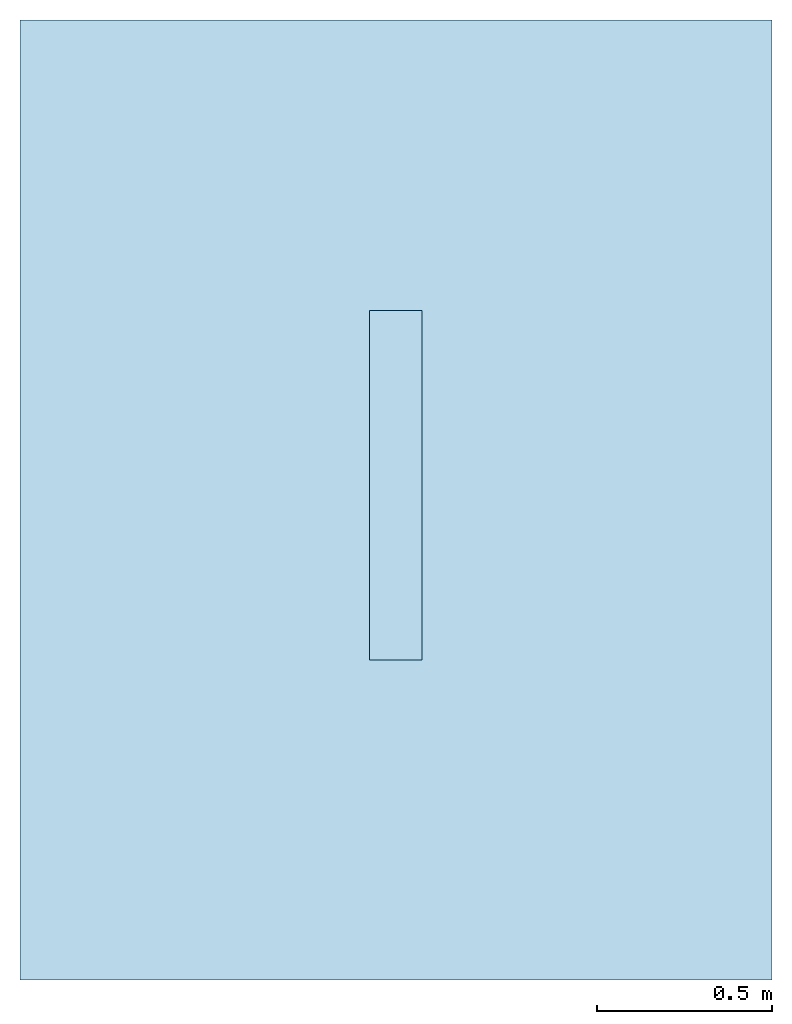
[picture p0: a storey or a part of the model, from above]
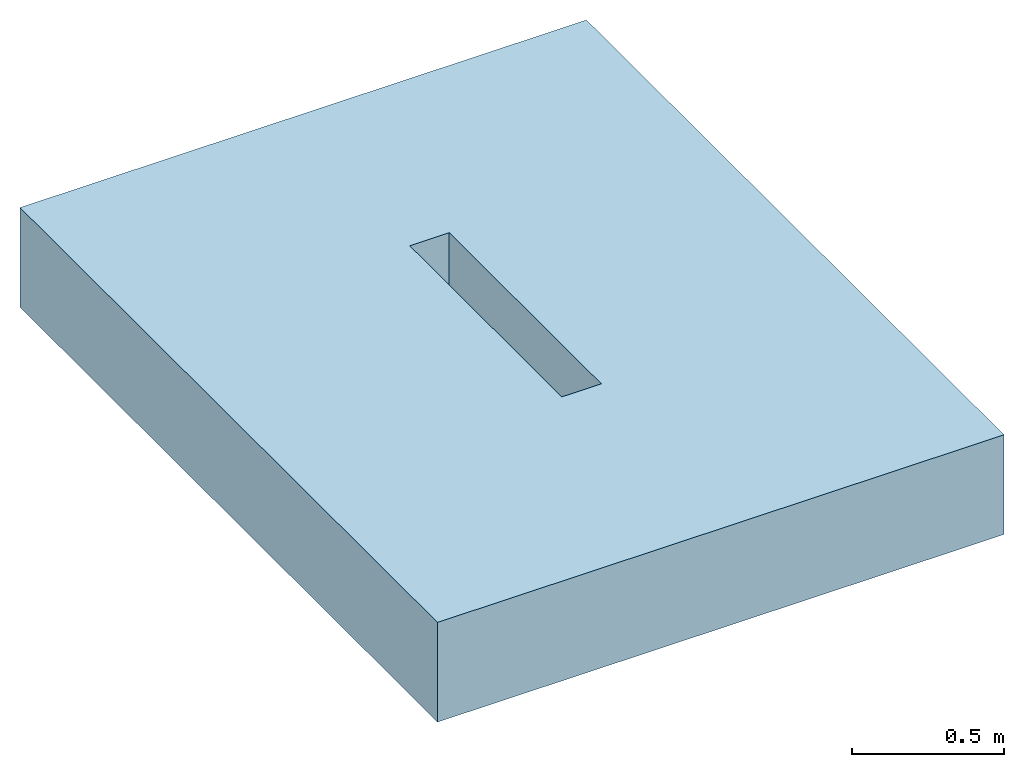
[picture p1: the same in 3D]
Properties of the parts of a building model (IFC2X3)

# File
Description: ViewDefinition [CoordinationView]
File name: 4966 - RH BS transition kerb - 1000mm LG.ifc
Time: 2013-09-18T16:27:48
Written by: Autodesk Revit 2013
Made in: 20120221_2030(x64)

# IfcProject, Project Number
LongName: Project Name; Phase: Project Status

# IfcSite, Default
RefLatitude: 42, 21, 30, 344238; RefLongitude: -71, -3, -35, -194702; RefElevation: 0 mm

# IfcBuilding
Pset_BuildingCommon - NumberOfStoreys: 2
Other - Project Name: Project Name; Project Number: Project Number; Project Status: Project Status; Project Address: Enter address here; Project Issue Date: Issue Date; Client Name: Owner

# IfcBuildingStorey (2)
Constraints - Elevation Base: 0
Graphics - Symbol at End 2 Default: yes; Symbol at End 1 Default: no; Line Pattern: Center; Line Weight: 1; Color: 0; Symbol: M_Level Head - Circle: M_Level Head - Circle
Identity Data - Structural: no; Building Story: yes
Dimensions - Computation Height: 0 mm
Name | LongName = Name | Elevation (mm) = Constraints, Elevation (mm)
T.O. Fnd. Wall | T.O. Fnd. Wall | -300
Level 1 | Level 1 | 0

# IfcBuildingElementProxy: 4966 - RH BS transition kerb - 1000mm LG, Civil-Drainage-Channel-ACO-KerbDrain-HB480(amar):4966 - RH BS transition kerb - 1000mm LG:4966 - RH BS transition kerb - 1000mm LG:481515
In: T.O. Fnd. Wall
Material: ACO Polymer Concrete.
Other - CreatedBy: www.aco.co.uk; Revision: 1
Green Building Properties - End Cap Recycled Material Content: N/A; Access Cover/Frame Recycled Material Content: N/A; Channel Recycled Material Content: 20% minimum; Access Cover/Frame Recyclable: N/A; Channel Recyclable: Fully recyclable; End Cap Recyclable: N/A
Constraints - Moves With Nearby Elements: no; Level: Level: Level 1
Dimensions - Volume: 38825786 mm3; Void Width: 150 mm; Void Start I/O: 0 mm; junction void depth: 2000 mm; Mitre Small End: 487 mm; Void End I/O: 150 mm; Mitre Void End: -7885 mm; Straight Void Start: 0 mm; Junction End: 150 mm; Mitre Long end: 500 mm; Void Depth: -355 mm; Mitre Void Start: -7880 mm; Junction Start: 0 mm; I/O endcap void depth: 2000 mm; Void Length: 1000 mm
Phasing - Phase Created: Phase 1
Pset_BuildingElementProxyCommon - Reference: 4966 - RH BS transition kerb - 1000mm LG
Identity Data - Product brochure: http://www.aco.co.uk/download.php?id=120; Installation guidelines: http://www.aco.co.uk/download.php?id=120; Type Comments: ACO KerbDrain HB480 half battered RH bus stop transition kerb unit 1000mm long; Maintenance guidelines: http://www.aco.co.uk/download.php?id=120; e-mail Sales: customersupport@aco.co.uk; OmniClass Title: Rainwater Removal; Manufacturer: ACO Technologies plc - ACO Water Management Division; Price: POA - contact ACO; Model Description: Combined kerb and drainage system; Product Code: 4966; Address: ACO Business Park, Hitchin Road, Shefford, Bedfordshire, United Kingdom SG17 5TE; URL: www.aco.co.uk; Assembly Description: Rain Water Drainage; e-mail Technical: technical@aco.co.uk; Assembly Code: D2040; Product Page URL: http://www.aco.co.uk/product_detail.php?id=3; Fax: +44 (0)1462 815895; Telephone: +44 (0)1462 816666; OmniClass Number: 23.70.50.24; Model: ACO KerbDrain HB480; Cost: 0
Materials and Finishes - End Cap Colour: N/A; Access Cover/Frame Finish: N/A; Access Cover/Frame Material: N/A; Connection Pipe Material Colour: N/A; Access Cover/Frame Colour: N/A; Channel Material: Vienite® Synthetic Resin Concrete; End Cap Material: N/A; Channel Colour: Grey; Connection Pipe Material: N/A
Data - Connection Pipe O.D: N/A; Product Dimensions: 1000mm x 150mm x 535/480mm (LxWxH); Load Class: A 15 - D 400; Product Standard: BS EN 1433:2002, CE marked, Kitemarked; Drainage Slot Width: N/A; Installation - Concrete Grade: Refer to brochure; Concrete Surround Volume - Load Class A 15 - D 400 - Concrete Pavement: 0.20m³/m; Concrete Surround Volume - Load Class A 15 - D 400 - Grass or Asphalt Pavement: 0.19m³/m; Channel C.S.A: 0.04m²; Hydraulic Performance: http://www.aco.co.uk/download.php?id=120; Drainage Slot Intake area: N/A; Product Weight: 83.4 kg; ACO Hydraulic Design Software: http://www.acodesign.co.uk; Invert Depth: 510/455mm
Construction - Junction access unit: no; Junction end cap: no; Bus stop kerb: no; 10-8m external mitre: no; 25-11m external mitre: no; perforated centre stone: no; Access Unit: no; RH inlet/outlet end cap: no; Closing end cap: no; RH drop kerb: no; LH drop kerb: no; KDHB480 500_blindunit: no; 7-6m external mitre: no; Centre Stone: no; Junction channel: no; RH BS transition kerb: yes; HB480-500: no; cable loop: no; LH inlet/outlet end cap: no; 25-11m internal mitre: no; LH BS transition kerb: no
General - TagNumber: 0.000000; SerialNumber: 0.000000

# IfcOpeningElement: Opening (3)
In: Level 1
Structural - Structural: no; Enable Analytical Model: no
Dimensions - Area: 5901750 mm2; Thickness: 400 mm; Perimeter: 9790 mm; Volume: 2307450000 mm3
Constraints - Room Bounding: yes; Related to Mass: no; Level: Level: Level 1; Height Offset From Level: 0 mm
Phasing - Phase Created: Phase 1
Analytical Properties - Absorptance: 0.1; Roughness: 1; Heat Transfer Coefficient (U): 2.0925; Thermal Resistance (R): 0.477897; Thermal mass: 543920
Graphics - Coarse Scale Fill Color: 0
Construction - Default Thickness: 400 mm; Function: 0
Materials and Finishes - Structural Material: Earth

# IfcSlab: Floor:Generic Floor - 400mm, Floor:Generic Floor - 400mm:136426
In: Level 1
PredefinedType: FLOOR; Material: Earth 400 mm
Structural - Structural: no; Enable Analytical Model: no
Dimensions - Area: 5901750 mm2; Thickness: 400 mm; Perimeter: 9790 mm; Volume: 2307450000 mm3
Constraints - Room Bounding: yes; Related to Mass: no; Level: Level: Level 1; Height Offset From Level: 0 mm
Phasing - Phase Created: Phase 1
Pset_SlabCommon - Reference: Generic Floor - 400mm; IsExternal: no; LoadBearing: yes
Analytical Properties - Absorptance: 0.1; Roughness: 1; Heat Transfer Coefficient (U): 2.0925; Thermal Resistance (R): 0.477897; Thermal mass: 543920
Graphics - Coarse Scale Fill Color: 0
Construction - Default Thickness: 400 mm; Function: 0
Materials and Finishes - Structural Material: Earth
